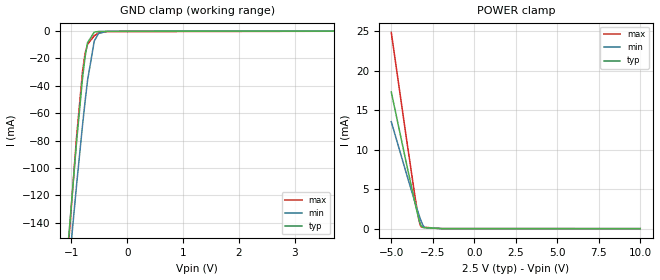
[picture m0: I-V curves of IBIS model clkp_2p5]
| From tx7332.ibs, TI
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|   clkp_2p5 Model
[Model]   clkp_2p5
Model_type   Input
Vinl = 0.625
Vinh = 1.875
|   typ   min   max
C_comp   10.038pF   9.155pF   10.512pF
[Model spec]
|subparameter
Vinl   0.625   0.6   0.65
Vinh   1.875   1.8   1.95
| Where Nom  PVT is Nominal Process, 2.5V, 27C
|   Fast PVT is Strong Process,  2.6V, 0C
|   Slow PVT is Weak Process,   2.4V, 100C
[Voltage Range]   2.5   2.4   2.6
|Junction Temperature
[Temperature Range]   27   100   0
[Power Clamp Reference]   2.5   2.4   2.6
[GND Clamp Reference]   0   0   0
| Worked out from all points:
|   GND clamp passes 1 mA (typ) near -0.58 V on its own axis
|   POWER clamp passes 1 mA (typ) near -3.31 V on its own axis
[GND Clamp]
|   Voltage   I(typ)   I(min)   I(max)
-5V       -2.315A    -2.046A    -2.569A
-1.13V    -192.6mA   -210.6mA   -200.3mA
-1.1V     -177.1mA   -197.1mA   -183.2mA
-1.07V    -161.7mA   -183.8mA   -166.2mA
-905mV    -80.27mA   -111.9mA   -76.85mA
-800mV    -34.8mA    -69.04mA   -29.89mA
-755mV    -19.39mA   -51.99mA   -16.83mA
-710mV    -8.793mA   -36.32mA   -10.05mA
-590mV    -1.16mA    -7.64mA    -3.743mA
-515mV    -650.1uA   -2.162mA   -1.741mA
-365mV    -545.5uA   -524.1uA   -778.9uA
10V       0A         0A         0A
[POWER Clamp]
|   Voltage   I(typ)   I(min)   I(max)
-5V       17.31mA    13.54mA    24.84mA
-4.1V     8.38mA     7.058mA    11.62mA
-3.575V   3.315mA    3.368mA    4.13mA
-3.44V    2.085mA    2.454mA    2.336mA
-3.335V   1.197mA    1.769mA    1.1mA
-3.26V    650.2uA    1.302mA    461.1uA
-3.2V     328.2uA    950.9uA    242.3uA
-3.08V    136.7uA    372.4uA    185.3uA
-2.975V   120.9uA    137.6uA    168.6uA
-1.94V    2.883uA    1.369uA    5.878uA
10V       0A         0A         0A
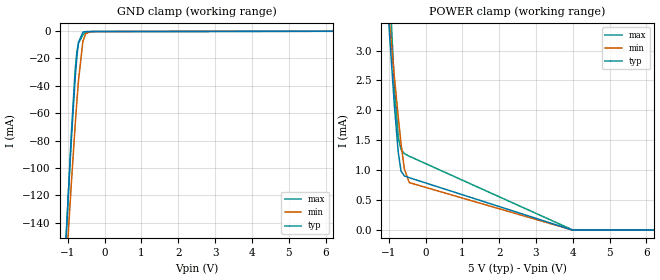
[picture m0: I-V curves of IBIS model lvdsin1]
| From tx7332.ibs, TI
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|   lvdsin1 Model
[Model]   lvdsin1
Model_type   Input
Vinl = 1.25
Vinh = 3.75
|   typ   min   max
C_comp   7.685pF   7.172pF   7.864pF
| Where Nom  PVT is Nominal Process, 5.0V, 27C
|   Fast PVT is Strong Process,  5.1V, 0C
|   Slow PVT is Weak Process,   4.9V, 100C
[Voltage Range]   5   4.9   5.1
|Junction Temperature
[Temperature Range]   27   100   0
[Power Clamp Reference]   5   4.9   5.1
[GND Clamp Reference]   0   0   0
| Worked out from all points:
|   GND clamp passes 1 mA (typ) near -0.61 V on its own axis
|   POWER clamp passes 1 mA (typ) near -0.67 V on its own axis
[GND Clamp]
|   Voltage   I(typ)   I(min)   I(max)
-5V       -2.315A    -2.046A    -2.57A
-1.25V    -255mA     -264.8mA   -268.2mA
-1.1V     -176.7mA   -197mA     -181.5mA
-1.07V    -161.3mA   -183.6mA   -164.5mA
-905mV    -79.81mA   -111.7mA   -75.24mA
-800mV    -34.28mA   -68.79mA   -28.46mA
-755mV    -18.86mA   -51.73mA   -15.51mA
-710mV    -8.26mA    -36.05mA   -8.788mA
-590mV    -786.7uA   -7.364mA   -2.671mA
-515mV    -381.1uA   -1.919mA   -1.029mA
-365mV    -295.1uA   -303uA     -413.3uA
10V       0A         0A         0A
[POWER Clamp]
|   Voltage   I(typ)   I(min)   I(max)
-5V       43.54mA    32.83mA    63.59mA
-1.415V   7.472mA    6.549mA    10.23mA
-1.235V   5.707mA    5.261mA    7.632mA
-1.1V     4.405mA    4.306mA    5.719mA
-1.055V   3.977mA    3.991mA    5.095mA
-845mV    2.078mA    2.558mA    2.41mA
-740mV    1.297mA    1.885mA    1.552mA
-665mV    984.4uA    1.446mA    1.347mA
-575mV    904.1uA    1.022mA    1.277mA
-440mV    873.9uA    791.4uA    1.233mA
3.985V    0A         0A         3.992uA
10V       0A         0A         0A
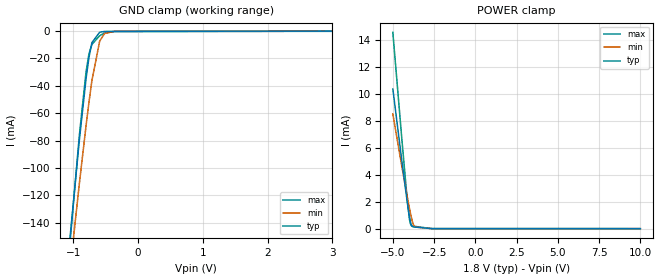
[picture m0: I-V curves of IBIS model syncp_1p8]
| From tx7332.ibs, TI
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|   sync_1p8 Model
[Model]   syncp_1p8
Model_type   Input
Vinl = 0.45
Vinh = 1.35
|   typ   min   max
C_comp   9.283pF   8.623pF   9.587pF
[Model spec]
|subparameter
Vinl   0.45   0.425   0.475
Vinh   1.35   1.275   1.425
| Where Nom  PVT is Nominal Process, 1.8V, 27C
|   Fast PVT is Strong Process,  1.9V, 0C
|   Slow PVT is Weak Process,   1.7V, 100C
[Voltage Range]   1.8   1.7   1.9
|Junction Temperature
[Temperature Range]   27   100   0
[Power Clamp Reference]   1.8   1.7   1.9
[GND Clamp Reference]   0   0   0
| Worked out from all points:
|   GND clamp passes 1 mA (typ) near -0.58 V on its own axis
|   POWER clamp passes 1 mA (typ) near -4.01 V on its own axis
[GND Clamp]
|   Voltage   I(typ)   I(min)   I(max)
-5V       -2.315A    -2.046A    -2.569A
-1.13V    -192.6mA   -210.6mA   -200.3mA
-1.1V     -177.1mA   -197.1mA   -183.2mA
-1.07V    -161.7mA   -183.8mA   -166.2mA
-905mV    -80.27mA   -111.9mA   -76.85mA
-800mV    -34.8mA    -69.04mA   -29.89mA
-755mV    -19.39mA   -51.99mA   -16.83mA
-710mV    -8.793mA   -36.32mA   -10.05mA
-590mV    -1.16mA    -7.64mA    -3.743mA
-515mV    -650.1uA   -2.162mA   -1.741mA
-365mV    -545.5uA   -524.1uA   -779uA
10V       0A         0A         0A
[POWER Clamp]
|   Voltage   I(typ)   I(min)   I(max)
-5V       10.35mA    8.489mA    14.54mA
-4.46V    5.07mA     4.651mA    6.719mA
-4.16V    2.263mA    2.588mA    2.593mA
-4.07V    1.482mA    1.994mA    1.485mA
-3.995V   891.6uA    1.516mA    718.1uA
-3.95V    587.3uA    1.241mA    404.9uA
-3.89V    290.1uA    895.3uA    228.5uA
-3.83V    162.7uA    585.5uA    195.2uA
-3.755V   131.5uA    287.8uA    181.3uA
-3.65V    118.1uA    120.8uA    164.7uA
-2.63V    1.77uA     350.7nA    4.332uA
10V       0A         0A         0A
